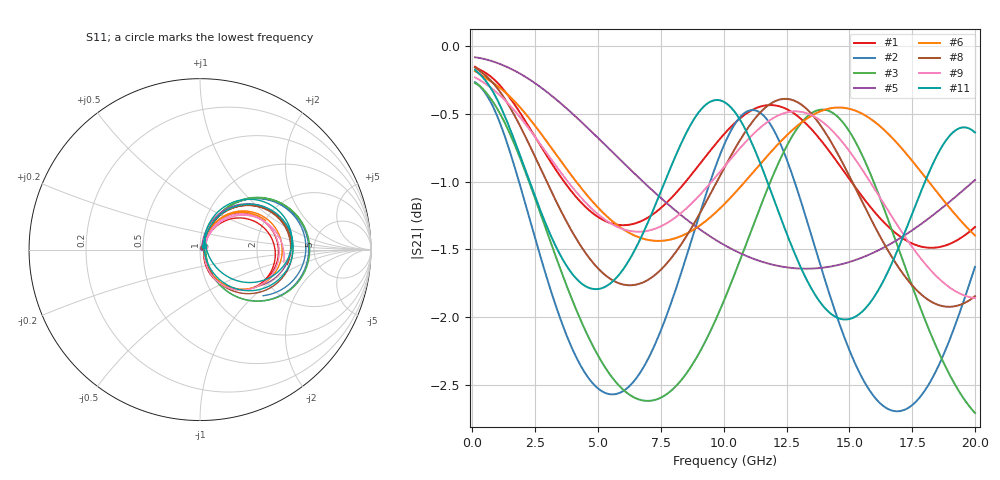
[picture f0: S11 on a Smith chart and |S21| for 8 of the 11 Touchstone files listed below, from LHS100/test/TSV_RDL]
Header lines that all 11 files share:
! Touchstone file exported from HFSS 2026.1.0
!  Design:  TSV_RDL
! Variables:
! Terminal data exported
# GHz S MA R 50.000000
Fixed: h_ox = 20um, h_rdl = 5um, h_via = 3um, m_sub = 200um, s_tmrdl = 10um, w_sub = 500um
Also varied, not listed: x_tsv_center2, x_tsv_center3, x_tsv_center4, x_tsv_center5, x_tsv_center6
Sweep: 100 MHz to 20 GHz
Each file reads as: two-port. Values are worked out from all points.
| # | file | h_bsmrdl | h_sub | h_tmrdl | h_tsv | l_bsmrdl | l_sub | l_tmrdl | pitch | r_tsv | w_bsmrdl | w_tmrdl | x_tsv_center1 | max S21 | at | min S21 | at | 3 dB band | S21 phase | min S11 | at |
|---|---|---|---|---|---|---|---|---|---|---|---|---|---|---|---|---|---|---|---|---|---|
| 1 | dut1.s2p | 5.18um | 77.09um | 5.94um | 77.09um | 448.6um | 5218.2um | 827.78um | 49.79um | 3.22um | 24.08um | 29.68um | 842.62um | -0.15 dB | 100 MHz | -1.5 dB | 18.3 GHz | 100 MHz-20 GHz | -150 deg at 10.1 GHz | -32.9 dB | 12.1 GHz |
| 2 | dut4.s2p | 5.99um | 66.93um | 4.41um | 66.93um | 720.72um | 5551.68um | 719.06um | 54.64um | 2.16um | 20.17um | 17.59um | 727.855um | -0.27 dB | 100 MHz | -2.7 dB | 16.9 GHz | 100 MHz-20 GHz | -155 deg at 10.1 GHz | -29.3 dB | 11.3 GHz |
| 3 | dut6.s2p | 2.7um | 56.76um | 5.75um | 56.76um | 931.78um | 4453.5um | 295.28um | 47.48um | 8.48um | 15.58um | 10.1um | 300.33um | -0.27 dB | 100 MHz | -2.7 dB | 20 GHz | 100 MHz-20 GHz | -121 deg at 10.1 GHz | -29.2 dB | 14.1 GHz |
| 4 | dut7.s2p | 5.72um | 61.28um | 2.64um | 61.28um | 786.11um | 3561.7um | 178.14um | 59.03um | 14.76um | 11.78um | 18.49um | 187.385um | -0.16 dB | 100 MHz | -2.7 dB | 8.5 GHz | 100 MHz-20 GHz | -101 deg at 10.1 GHz | -32.0 dB | 100 MHz |
| 5 | dut9.s2p | 4.06um | 98.48um | 4.61um | 98.48um | 149.71um | 1824.16um | 220.38um | 53.82um | 9.25um | 19.59um | 11.58um | 226.17um | -0.08 dB | 100 MHz | -1.6 dB | 13.3 GHz | 100 MHz-20 GHz | -67 deg at 10.1 GHz | -38.1 dB | 100 MHz |
| 6 | dut10.s2p | 3.76um | 52.51um | 3.14um | 52.51um | 600.43um | 4305.38um | 493.54um | 40.17um | 4.32um | 21.22um | 22.09um | 504.585um | -0.19 dB | 100 MHz | -1.4 dB | 7.4 GHz | 100 MHz-20 GHz | -118 deg at 10.1 GHz | -32.2 dB | 14.9 GHz |
| 7 | dut13.s2p | 5.23um | 79.8um | 3.73um | 79.8um | 327.27um | 3628.48um | 532.2um | 47.34um | 4.69um | 12.66um | 26.63um | 545.515um | -0.15 dB | 100 MHz | -1.7 dB | 8.4 GHz | 100 MHz-20 GHz | -107 deg at 10.1 GHz | -33.5 dB | 100 MHz |
| 8 | dut14.s2p | 4.87um | 59.69um | 3.82um | 59.69um | 299.95um | 5011.17um | 895.4um | 53.04um | 10.23um | 18.19um | 25.05um | 907.925um | -0.16 dB | 100 MHz | -1.9 dB | 19 GHz | 100 MHz-20 GHz | -138 deg at 10.1 GHz | -32.5 dB | 12.6 GHz |
| 9 | dut15.s2p | 2.85um | 81.66um | 4.93um | 81.66um | 875.63um | 4448.61um | 326.24um | 39.83um | 12.02um | 14.92um | 24um | 338.24um | -0.23 dB | 100 MHz | -1.9 dB | 20 GHz | 100 MHz-20 GHz | -137 deg at 10.1 GHz | -31.3 dB | 13.2 GHz |
| 10 | dut18.s2p | 3.32um | 94.32um | 5.14um | 94.32um | 979.94um | 7343.27um | 971.77um | 45.53um | 12.89um | 26.01um | 12.78um | 978.16um | -0.29 dB | 100 MHz | -2.5 dB | 18.6 GHz | 100 MHz-20 GHz | 128 deg at 10.1 GHz | -30.8 dB | 7.5 GHz |
| 11 | dut19.s2p | 5.6um | 67.95um | 4.07um | 67.95um | 830.01um | 6055.34um | 754.9um | 58.25um | 13.45um | 29.22um | 19.35um | 764.575um | -0.18 dB | 100 MHz | -2.0 dB | 14.8 GHz | 100 MHz-20 GHz | -178 deg at 10.1 GHz | -31.9 dB | 9.9 GHz |
